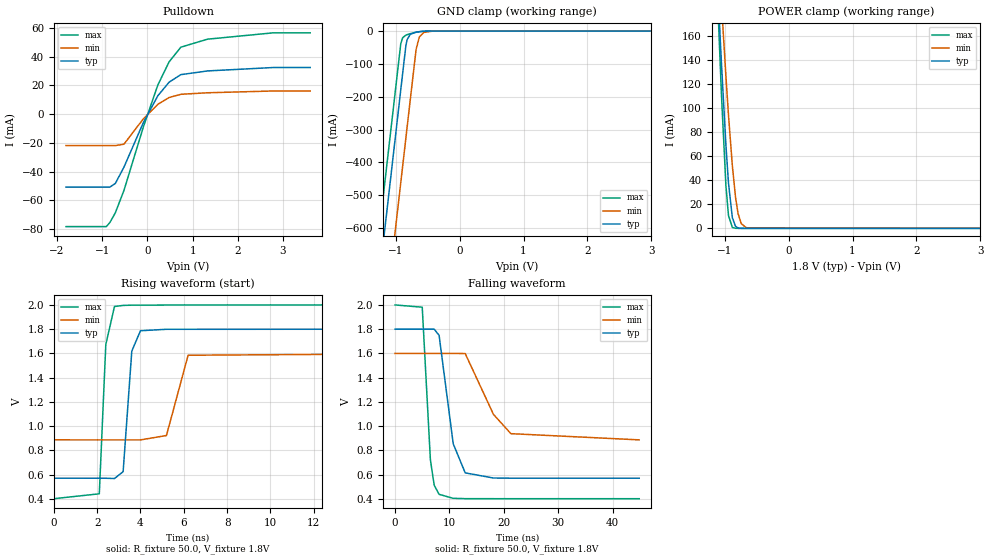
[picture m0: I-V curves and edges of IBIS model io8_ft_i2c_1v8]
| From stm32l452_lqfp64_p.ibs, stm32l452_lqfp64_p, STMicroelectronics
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[Model]   io8_ft_i2c_1v8
Model_type I/O_open_drain
Polarity   Non-Inverting
Enable   Active-Low
| CAP_THRESHOLD on pad IOFT is "UDTCAPC" :
| Rising=30.00f vddiom   Falling=70.00f vddiom
| C_comp min and max val. don't necessarily correlate with the min and max pvt
| but are the smallest and greatest pad capacitance found.
| var   typ   min   max
C_comp   2.28842pF  2.27465pF  2.35140pF
|C_comp_pulldown   2.28842pF  2.27465pF  2.35140pF
Vinl = 480.0mV
Vinh = 1.4V
Vmeas = 900.0mV   | Reference voltage for timing measurements
Cref  = 50.0pF   | Timing specification test load capacitance value
Rref  = 100.0MOhm   | Timing specification test load resistance value
Vref  = 1700.0mV   | Timing specification test load voltage
[Model Spec]
| TIME_THRESHOLD on pin ZIV12 is "CMOS" :
| Rising=50.00f vdd   Falling=50.00f vdd
Vinl 728.70000mV 655.70000mV 817.70000mV
Vinh 1.06430V 949.30000mV 1.16330V
| variable   typ   min   max
[Temperature Range] 25.0 140.0 -40.0
| variable   typ   min   max
[Voltage Range] 1.8V 1.6V 2.0V
| variable   typ   min   max
[POWER Clamp Reference] 1.8V 1.6V 2.0V
| variable   typ   min   max
[GND Clamp Reference] 0V 0V 0V
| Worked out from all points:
|   slope of the pulldown table from 0 to 0.27 V, typ, clamps not added: 18.6 ohm
|   GND clamp passes 1 mA (typ) near -0.58 V on its own axis
|   POWER clamp passes 1 mA (typ) near -0.81 V on its own axis
|   rising waveform, R_fixture 50.0, V_fixture 1.8V: 20-80 % time 241ps typ, 391ps min, 174ps max; typ from 0.571 V to 1.8 V
|   falling waveform, R_fixture 50.0, V_fixture 1.8V: 20-80 % time 2.2ns typ, 4.44ns min, 1.11ns max; typ from 1.8 V to 0.571 V
[POWER Clamp]
-1.8V     1.053A     943.1mA    1.262A
-1.11V    202.2mA    242.3mA    190.9mA
-1.09V    180mA      223.6mA    163.4mA
-1.05V    136.9mA    187mA      110.9mA
-980mV    68.91mA    126.1mA    35.23mA
-940mV    37.57mA    94.11mA    10.65mA
-880mV    8.969mA    52.17mA    807.4uA
-830mV    1.697mA    25.82mA    75.79uA
-790mV    394.2uA    12.22mA    11.25uA
-740mV    61.25uA    3.879mA    1.034uA
-660mV    3.073uA    483.4uA    22.7nA
3.6V      0A         0A         0A
[GND Clamp]
-1.8V     -1.676A    -1.958A    -1.532A
-920mV    -179.6mA   -462.3mA   -38.92mA
-890mV    -128.6mA   -411.3mA   -20.43mA
-840mV    -45.1mA    -326.3mA   -12.52mA
-820mV    -26.23mA   -292.3mA   -11.04mA
-770mV    -9.555mA   -207.3mA   -8.082mA
-680mV    -3.389mA   -56.17mA   -3.835mA
-630mV    -1.938mA   -18.22mA   -2.1mA
-560mV    -677.9uA   -4.349mA   -613.5uA
-420mV    -19.92uA   -200.8uA   -7.526uA
3.6V      453.8pA    104.4nA    315.2pA
| variable   typ   min   max
[Pullup Reference] 1.8V 1.6V 2.0V
| variable   typ   min   max
[Pulldown Reference] 0V 0V 0V
[Pulldown]
-1.8V     -50.74mA   -21.88mA   -78.23mA
-910mV    -50.74mA   -21.88mA   -78.23mA
-830mV    -50.74mA   -21.88mA   -75.4mA
-710mV    -48.24mA   -21.88mA   -68.66mA
-520mV    -36.95mA   -20.94mA   -53.18mA
-90mV     -5.881mA   -3.274mA   -8.972mA
230mV     12.73mA    6.81mA     20.2mA
480mV     22.23mA    11.54mA    36.37mA
740mV     27.46mA    13.79mA    46.57mA
1.33V     30.03mA    14.84mA    52.12mA
2.78V     32.4mA     16.09mA    56.53mA
3.6V      32.4mA     16.09mA    56.54mA
[Ramp]
dV/dt_r 737.55035mV/223.95894ps 427.73762mV/389.0149ps 958.89815mV/160.97775ps
dV/dt_f 737.58711mV/2.20176ns 427.79315mV/4.43833ns 958.92397mV/1.11352ns
R_load = 50.0
| Removed startup time: 0s 0s 0s  .
| Removed end time: 19.9ns.
[Rising Waveform]
R_fixture   = 50.0
V_fixture   = 1.8V
V_fixture_min = 1.6V
V_fixture_max = 2.0V
0s        570.7mV    887mV      401.8mV
2.1ns     570.6mV    886.9mV    442.2mV
2.4ns     570.5mV    886.9mV    1.673V
2.8ns     568.3mV    886.9mV    1.987V
3.2ns     624.9mV    886.9mV    1.996V
3.6ns     1.619V     886.9mV    1.998V
4ns       1.787V     886.8mV    1.998V
5.2ns     1.799V     922.9mV    1.999V
6.2ns     1.799V     1.585V     2V
19.9ns    1.8V       1.6V       2V
| Removed startup time: 0s 0s 0s  .
| Removed end time: 44.9ns.
[Falling Waveform]
R_fixture   = 50.0
V_fixture   = 1.8V
V_fixture_min = 1.6V
V_fixture_max = 2.0V
0s        1.8V       1.6V       2V
5ns       1.8V       1.6V       1.981V
6.5ns     1.8V       1.6V       721.6mV
7.2ns     1.8V       1.6V       512.7mV
8.1ns     1.749V     1.6V       437.8mV
10.7ns    854.5mV    1.6V       404.8mV
12.9ns    614.9mV    1.599V     402.2mV
18.1ns    572.4mV    1.097V     401.8mV
21.3ns    570.9mV    938.2mV    401.8mV
44.9ns    570.7mV    887mV      401.8mV
